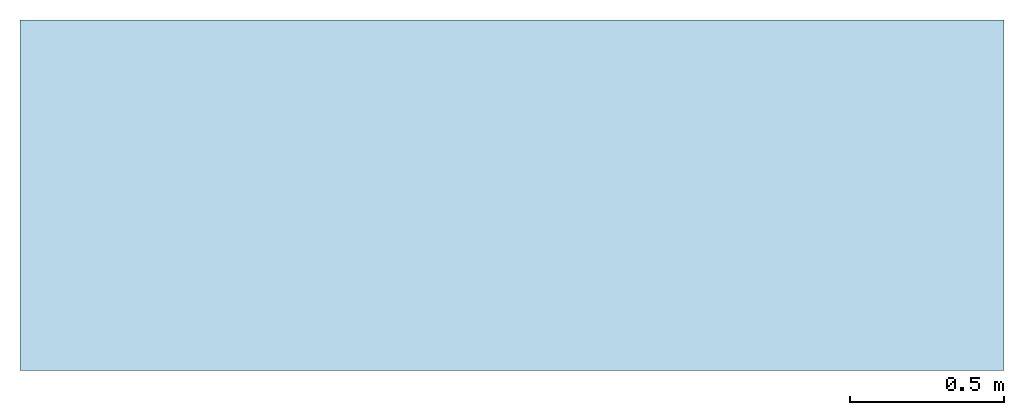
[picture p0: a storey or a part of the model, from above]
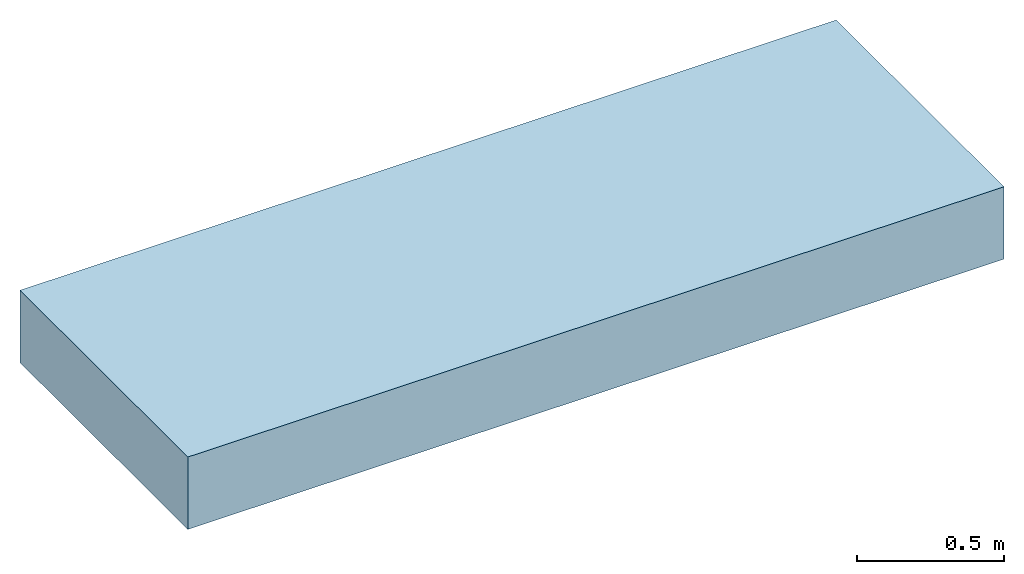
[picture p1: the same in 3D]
Properties of the parts of a building model (IFC2X3)

# File
Description: ViewDefinition [CoordinationView_V2.0, QuantityTakeOffAddOnView], RevitIdentifiers [ContentGUID: 704ee8e6-b7a5-4cdf-b516-c9cadaf13e75, VersionGUID: 9f17e6e7-f3a3-40c8-a4d2-a42c9d882847, NumberOfSaves: 43], CoordinateReference [CoordinateBase: Shared Coordinates, ProjectSite: Internal]
File name: Solucion panel prefabricado stud frame.ifc
Time: 2026-03-16T14:00:17+01:00
Written by: ODA SDAI 24.6
Made in: Autodesk Revit 24.3.40.26 (ESP) - IFC 24.3.20.0

# IfcProject, 000000
LongName: Solución panel prefabricado stud frame

# IfcSite, Default
RefLatitude: 40, 25, 13, 9643; RefLongitude: -3, -42, -20, -772056; RefElevation: 0 m
Otra - Categoría: Información de proyecto; Dirección de proyecto: Parque Empresarial de A Pontenova , Parcelas 33-39 , 27720 · A Pontenova · (Lugo); Fecha de emisión de proyecto: 09-02-2026; Nombre de cliente: Recense; Nombre de proyecto: Solución panel prefabricado stud frame; Número de proyecto: 000000
Datos de identidad - Autor: Deliprogal; Descripción de organización: Fijaciones a medida para prefabricado; Nombre de organización: Recense

# IfcBuilding
Pset_BuildingCommon - NumberOfStoreys: 2
Otra - Categoría: Información de proyecto; Dirección de proyecto: Parque Empresarial de A Pontenova , Parcelas 33-39 , 27720 · A Pontenova · (Lugo); Fecha de emisión de proyecto: 09-02-2026; Nombre de cliente: Recense; Nombre de proyecto: Solución panel prefabricado stud frame; Número de proyecto: 000000
Datos de identidad - Autor: Deliprogal; Descripción de organización: Fijaciones a medida para prefabricado; Nombre de organización: Recense

# IfcBuildingStorey: Nivel:8mm Head (2)
Otra - Categoría: Niveles; Familia: Nivel; Familia y tipo: Nivel: 8mm Head; ID de tipo: 305; Tipo: 8mm Head
Cotas - Altura de cálculo: 0 m
Datos de identidad - Estructura: no; Planta de edificio: yes
Otra(Tipo) - Categoría: Niveles; Nombre de familia: Nivel
Restricciones(Tipo) - Base de elevación: Punto base del proyecto
Gráficos(Tipo) - Color: 12615680; Grosor de línea: 1; Patrón de línea: Dash dot; Símbolo en extremo 1 por defecto: no; Símbolo en extremo 2 por defecto: yes
Datos de identidad(Tipo) - Nombre de tipo: 8mm Head
Name | LongName = Nombre | Elevation (m) = Elevación (m)
L0 | L0 | 0
L1 | L1 | 3

# IfcBuildingElementProxy: Panel Hormigón:Panel Hormigón, Panel Hormigón:Panel Hormigón:3763083
In: L0
Type - Material: Hormigón reforzado con fibra de vidrio, Acero AISI 1022
Type - Otra - Categoría: Modelos genéricos; Nombre de familia: Panel Hormigón
Type - Restricciones - Elevación por defecto: 13.1234 m
Type - Datos de identidad - Nombre de tipo: Panel Hormigón
Pset_BuildingElementProxyCommon - Reference: Panel Hormigón; sets with these values: 2
Otra - Familia: Panel Hormigón; Familia y tipo: Panel Hormigón: Panel Hormigón; ID de tipo: 3674676; Tipo: Panel Hormigón
Restricciones - Desfase desde el anfitrión: -0.15 m; Elevación desde el nivel: 0 m; Plano de trabajo: <no asociado>
Cotas - Área: 14.7895 m2; Volumen: 0.111377 m3
Proceso por fases - Fase de creación: New

# IfcCovering: Techo compuesto:Aislamiento, Techo compuesto:Aislamiento:3635725
In: L0
Type - PredefinedType: CEILING
Type - Otra - Categoría: Techos; Nombre de familia: Techo compuesto
Type - Construcción - Grosor: 0.08 m
Type - Gráficos - Color de relleno de detalle bajo: 0
Type - Datos de identidad - Nombre de tipo: Aislamiento
Type - Propiedades analíticas - Absortancia: 0.7; Aspereza: 3; Coeficiente de transferencia de calor (U): 0.425 kg/K/s3; Masa térmica: 11360 kg/K/s2; Resistencia térmica (R): 2.35294 s3*K/kg
Type - Pset_CoveringCommon - TotalThickness: 0.08 m
Material: Lana de roca 0.08 m
Pset_CoveringCommon - Reference: Aislamiento; sets with these values: 2
BaseQuantities - GrossCeilingArea: 1.4356 m2
Otra - Familia: Techo compuesto; Familia y tipo: Techo compuesto: Aislamiento; ID de tipo: 3635518; Tipo: Aislamiento
Restricciones - Delimitación de habitación: yes; Nivel: L0; Desfase de altura desde nivel: 2.61 m
Cotas - Área: 1.4356 m2; Perímetro: 4.9 m; Volumen: 0.114848 m3
Proceso por fases - Fase de creación: New

# IfcCovering: Techo compuesto:Placa, Techo compuesto:Placa:3635732
In: L0
Type - PredefinedType: CEILING
Type - Otra - Categoría: Techos; Nombre de familia: Techo compuesto
Type - Construcción - Grosor: 0.01 m
Type - Gráficos - Color de relleno de detalle bajo: 0
Type - Datos de identidad - Nombre de tipo: Placa
Type - Propiedades analíticas - Absortancia: 0.7; Aspereza: 3; Coeficiente de transferencia de calor (U): 51 kg/K/s3; Masa térmica: 10752 kg/K/s2; Resistencia térmica (R): 0.0196078 s3*K/kg
Type - Pset_CoveringCommon - TotalThickness: 0.01 m
Material: Enlucido 0.01 m
Pset_CoveringCommon - Reference: Placa; Finish: Enlucido;
Pset_QuantityTakeOff - Reference: Placa
BaseQuantities - GrossCeilingArea: 1.2672 m2
Otra - Familia: Techo compuesto; Familia y tipo: Techo compuesto: Placa; ID de tipo: 3635581; Tipo: Placa
Restricciones - Delimitación de habitación: yes; Nivel: L0; Desfase de altura desde nivel: 2.6 m
Cotas - Área: 1.2672 m2; Perímetro: 4.56 m; Volumen: 0.012672 m3
Proceso por fases - Fase de creación: New

# IfcElementAssembly: REC-AEM12-100:AEM12-100 (2)
In: L0
Type - Material: REC_Acero, S 275JR (Zincado)
Type - Otra - Categoría: Conexiones estructurales; Nombre de familia: REC-AEM12-100
Type - Restricciones - Elevación por defecto: 0 m
Type - Datos - Classification.Uniclass.Pr.Description: Bolts and accessories; Classification.Uniclass.Pr.Number: Pr_20_29_08
Type - Datos de identidad - Costo: 0; Creado por:: Deliprogal SL; Descripción: Anclaje M12; Fabricante: RECENSE; Fecha de Creacion:: 12/12/2025; Fecha Ultima Revision:: 16/03/2026; Modelo: AEM12-100; Nombre de tipo: AEM12-100; URL: https://recense.com/
Pset_QuantityTakeOff - Reference: AEM12-100
Otra - Familia: REC-AEM12-100; Familia y tipo: REC-AEM12-100: AEM12-100; ID de tipo: 3834086; Tipo: AEM12-100
Restricciones - Anfitrión: Panel Hormigón : Panel Hormigón; Se mueve con elementos cercanos: no
Datos - DPG_FABRICA: IL; DPG_NUMERO_OT: OT-
Cotas - Área: 0.00338965 m2; Volumen: 0.0000142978 m3
Proceso por fases - Fase de creación: New
Name (REC-AEM12-100:AEM12-100:...)
3767526
3793628

# IfcElementAssembly: REC-AEM12-140:AEM12-140 (2)
In: L0
Type - Material: REC_Acero, S 275JR (Zincado)
Type - Otra - Categoría: Conexiones estructurales; Nombre de familia: REC-AEM12-140
Type - Restricciones - Elevación por defecto: 0 m
Type - Datos - Classification.Uniclass.Pr.Description: Bolts and accessories; Classification.Uniclass.Pr.Number: Pr_20_29_08
Type - Datos de identidad - Costo: 0; Creado por:: Deliprogal SL; Descripción: https://recense.com/; Description_ESP: Anclaje M12; Fabricante: RECENSE; Fecha de Creacion:: 12/12/2025; Fecha Ultima Revision:: 16/03/2026; Modelo: AEM12-140; Nombre de tipo: AEM12-140
Pset_QuantityTakeOff - Reference: AEM12-140
Otra - Familia: REC-AEM12-140; Familia y tipo: REC-AEM12-140: AEM12-140; ID de tipo: 3781469; Tipo: AEM12-140
Restricciones - Se mueve con elementos cercanos: no; Anfitrión: Panel Hormigón : Panel Hormigón
Cotas - Área: 0.00414363 m2; Volumen: 0.0000188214 m3
Proceso por fases - Fase de creación: New
Name (REC-AEM12-140:AEM12-140:...)
3776366
3793606

# IfcElementAssembly: REC-AU12050M8EQ:AU12050M8EQ (4)
In: L0
Type - Material: REC_Acero, S 275JR (Zincado)
Type - Otra - Categoría: Conexiones estructurales; Nombre de familia: REC-AU12050M8EQ
Type - Restricciones - Elevación por defecto: 0 m
Type - Datos - Classification.Uniclass.Pr.Description: Anchors and componentsAnchors and components; Classification.Uniclass.Pr.Number: Pr_20_29_03
Type - Datos de identidad - Costo: 0; Creado por:: Deliprogal SL; Descripción: U-bolt M-8 120x50 mm equipped.; Description_ESP: Abarcón en U M-8 120x50 mm equipado.; Fabricante: RECENSE; Fecha de Creacion:: 03/02/2026; Fecha Ultima Revision:: 16/03/2026; Keynote_ESP: Sistema portante para sustentación de paneles de hormigón GRC tipo STUDFRAME en paramentos verticales.; Modelo: AU10040M8EQ; Nombre de tipo: AU12050M8EQ; Nota clave: Supporting system for fixing GRC STUDFRAME type panels to walls or other vertical concrete surface.; URL: https://abarcones.recense.com/ar/abarcones/abarcones-cuadrados/
Pset_QuantityTakeOff - Reference: AU12050M8EQ
Otra - Familia: REC-AU12050M8EQ; Familia y tipo: REC-AU12050M8EQ: AU12050M8EQ; ID de tipo: 3767338; Tipo: AU12050M8EQ
Restricciones - Se mueve con elementos cercanos: no; Anfitrión: Panel Hormigón : Panel Hormigón
Cotas - Área: 0.00322422 m2; Volumen: 0.00001157 m3
Proceso por fases - Fase de creación: New
Name (REC-AU12050M8EQ:AU12050M8EQ:...) | DPG_FOR_POS_ABARCON (m) = DPG_POS_ABARCON (m)
3767527 | 0.086
3776364 | 0.0965
3793605 | 0.0965
3793629 | 0.086

# IfcElementAssembly: REC-PA200406R:PA200406R (2)
In: L0
Type - Material: REC_Acero, S 275JR (Zincado)
Type - Otra - Categoría: Conexiones estructurales; Nombre de familia: REC-PA200406R
Type - Restricciones - Elevación por defecto: 0 m
Type - Datos - Classification.Uniclass.Pr.Description: Carbon steel anchor plates; Classification.Uniclass.Pr.Number: Pr_20_29_03_10
Type - Datos de identidad - Costo: 0; Creado por:: Deliprogal SL; Descripción: Angle plate 200x40x40x80x6 mm 2 slotted holes 15x9 mm.; Description_ESP: Pletina angular 200x40x80x6 mm 2 ranuras 15x9 mm.; Fabricante: RECENSE; Fecha de Creacion:: 20/01/2026; Fecha Ultima Revision:: 09/02/2026; Keynote_ESP: Sistema antivuelco para paneles de hormigón GRC tipo STUD FRAME.; Modelo: PA200406R; Nombre de tipo: PA200406R; Nota clave: Anti-tilt system for GRC concrete panels type STUD FRAME.; URL: https://prefabricados.recense.com/prefabricados/fijacion/fijacion-grc/grc-studframe/anclajes-antivuelco/pa200406r/
Pset_QuantityTakeOff - Reference: PA200406R
Otra - Familia: REC-PA200406R; Familia y tipo: REC-PA200406R: PA200406R; ID de tipo: 3767337; Tipo: PA200406R
Restricciones - Se mueve con elementos cercanos: no; Anfitrión: Ninguno
Cotas - Área: 0.0203081 m2; Volumen: 0.000107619 m3
Proceso por fases - Fase de creación: New
Name (REC-PA200406R:PA200406R:...)
3849143
3849144

# IfcElementAssembly: REC-PAA2005010R:PAA2005010R (2)
In: L0
Type - Material: REC_Acero, S 275JR (Zincado)
Type - Otra - Categoría: Conexiones estructurales; Nombre de familia: REC-PAA2005010R
Type - Restricciones - Elevación por defecto: 0 m
Type - Datos - Classification.Uniclass.Pr.Description: Carbon steel anchor plates; Classification.Uniclass.Pr.Number: Pr_20_29_03_10
Type - Datos de identidad - Costo: 0; Creado por:: Deliprogal SL; Descripción: Non-slip angle plate 200x50x80x80x10 mm with 2 slotted holes 15x9 mm.; Description_ESP: Pletina angular antideslizante 200x50x80x10 mm 2 ranuras 15x9 mm.; Fabricante: RECENSE; Fecha de Creacion:: 02/02/2026; Fecha Ultima Revision:: 09/02/2026; Keynote_ESP: Sistema de ménsula portante para paneles de hormigón GRC tipo STUD FRAME.; Modelo: PAA2005010R; Nombre de tipo: PAA2005010R; Nota clave: Supporting bracket system for GRC concrete panelsGRC concrete panels STUD FRAME type.; URL: https://prefabricados.recense.com/prefabricados/fijacion/fijacion-grc/grc-studframe/mensulas-portantes/paa2005010r/
Pset_QuantityTakeOff - Reference: PAA2005010R
Otra - Familia: REC-PAA2005010R; Familia y tipo: REC-PAA2005010R: PAA2005010R; ID de tipo: 3776105; Tipo: PAA2005010R
Restricciones - Se mueve con elementos cercanos: no
Cotas - Área: 0.0227408 m2; Volumen: 0.000180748 m3
Proceso por fases - Fase de creación: New
Name (REC-PAA2005010R:PAA2005010R:...) | Anfitrión
3781703 | Ninguno
3793610 | Panel Hormigón : Panel Hormigón

# IfcElementAssembly: REC-PD120308:PD120308 (2)
In: L0
Type - Material: REC_Acero, S 275JR (Zincado)
Type - Otra - Categoría: Conexiones estructurales; Nombre de familia: REC-PD120308
Type - Restricciones - Elevación por defecto: 0 m
Type - Datos - Classification.Uniclass.Pr.Description: Carbon steel anchor plates; Classification.Uniclass.Pr.Number: Pr_20_29_03_10
Type - Datos de identidad - Costo: 0; Creado por:: Deliprogal SL; Descripción: Toothed plate 120x30x8 mm.; Description_ESP: Pletina dentada 120x30x8 mm.; Fabricante: RECENSE; Fecha de Creacion:: 02/02/2026; Fecha Ultima Revision:: 09/02/2026; Keynote_ESP: Sistema de sustentación a forjado mediante anclajes portantes y antivuelco para paneles prefabricados de hormigón GRC tipo Studframe.; Modelo: PD120308; Nombre de tipo: PD120308; Nota clave: Supporting system for slab by means of load-bearing and anti-overturning anchors for precast concrete panels GRC Studframe type.; URL: https://prefabricados.recense.com/prefabricados/fijacion/fijacion-grc/grc-studframe/mensulas-portantes/paa2005010r/
Type - Texto - DPG_ANCLAJE_TIPO: ANCLAJE
Pset_QuantityTakeOff - Reference: PD120308
Otra - Familia: REC-PD120308; Familia y tipo: REC-PD120308: PD120308; ID de tipo: 3776109; Tipo: PD120308
Restricciones - Se mueve con elementos cercanos: no
Cotas - Área: 0.00536558 m2; Volumen: 0.0000252 m3
Proceso por fases - Fase de creación: New
Name (REC-PD120308:PD120308:...) | Anfitrión
3781702 | Ninguno
3793609 | Panel Hormigón : Panel Hormigón

# IfcFurnishingElement: REC_A_M8:REC_A_M8 (8)
In: L0
Type - Material: REC_Acero, S 275JR (Zincado)
Type - Otra - Categoría: Conexiones estructurales; Nombre de familia: REC_A_M8
Type - Restricciones - Elevación por defecto: 13.1234 m
Type - Datos de identidad - Modelo: A-M10; Nombre de tipo: REC_A_M8; URL: https://prefabricados.recense.com/prefabricados/fijacion/fijacion-grc/grc-studframe/anclajes-antivuelco/pa200406r/
Pset_QuantityTakeOff - Reference: REC_A_M8
Otra - Familia: REC_A_M8; Familia y tipo: REC_A_M8: REC_A_M8; ID de tipo: 3834089; Tipo: REC_A_M8
Restricciones - Se mueve con elementos cercanos: no; Anfitrión: Panel Hormigón : Panel Hormigón
Cotas - Área: 0.000324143 m2; Volumen: 6.24619e-07 m3
Proceso por fases - Fase de creación: New
Estructura - Recubrimiento de armadura: Rebar Cover 1 <25 mm>
Name (REC_A_M8:REC_A_M8:...) | Desfase desde el anfitrión (m)
3767528 | -0.010004
3767529 | -0.010004
3776367 | -0.0536447
3776368 | -0.0536447
3793607 | -0.0536447
3793608 | -0.0536447
3793630 | -0.010004
3793631 | -0.010004

# IfcOpeningElement: Opening (8)
In: L0
BaseQuantities - Depth: 0.08 m; Area: 0.00138596 m2
Pset_OpeningElementCommon - Reference: PA200406R; sets with these values: 2
Name (REC-PA200406R:PA200406R:...)
3849143:1
3849143:2
3849143:3
3849143:4
3849144:1
3849144:2
3849144:3
3849144:4

# IfcSlab: Suelo:DPG_Aislamiento Suelo, Suelo:DPG_Aislamiento Suelo:3607158
In: L0
Type - PredefinedType: FLOOR; Material: Lana de roca 0.04 m
Type - Otra - Categoría: Suelos; Nombre de familia: Suelo
Type - Construcción - Función: Interior; Grosor predeterminado: 0.04 m
Type - Gráficos - Color de relleno de detalle bajo: 0
Type - Datos de identidad - Nombre de tipo: DPG_Aislamiento Suelo
Type - Materiales y acabados - Material estructural: Lana de roca
Type - Propiedades analíticas - Absortancia: 0.7; Aspereza: 3; Coeficiente de transferencia de calor (U): 0.85 kg/K/s3; Masa térmica: 5680 kg/K/s2; Resistencia térmica (R): 1.17647 s3*K/kg
Type - Pset_SlabCommon - ThermalTransmittance: 0.85 kg/K/s3
Pset_QuantityTakeOff - Reference: DPG_Aislamiento Suelo; sets with these values: 2
Pset_SlabCommon - IsExternal: no; LoadBearing: no; PitchAngle: 0 deg; Reference: DPG_Aislamiento Suelo
BaseQuantities - Width: 1.64 m; Perimeter: 5.22 m; GrossArea: 1.5908 m2; NetArea: 1.5908 m2; GrossVolume: 0.063632 m3; NetVolume: 0.063632 m3
Otra - Familia: Suelo; Familia y tipo: Suelo: DPG_Aislamiento Suelo; ID de tipo: 3607200; Tipo: DPG_Aislamiento Suelo
Restricciones - Delimitación de habitación: yes; Nivel: L0; Relacionado con masa: no; Desfase de altura desde nivel: 0.04 m
Cotas - Área: 1.5908 m2; Elevación en parte inferior: 0 m; Elevación en parte inferior de núcleo: 0 m; Elevación en parte superior: 0.04 m; Elevación en parte superior de núcleo: 0.04 m; Grosor: 0.04 m; Perímetro: 5.22 m; Volumen: 0.063632 m3
Datos de identidad - Tiene asociación: no
Proceso por fases - Fase de creación: New
Estructura - Estructura: no

# IfcSlab: Suelo:DPG_Ceramica, Suelo:DPG_Ceramica:3607525
In: L0
Type - PredefinedType: FLOOR; Material: Azulejo, porcelana, 6 pulg. 0.01 m
Type - Otra - Categoría: Suelos; Nombre de familia: Suelo
Type - Construcción - Función: Interior; Grosor predeterminado: 0.01 m
Type - Gráficos - Color de relleno de detalle bajo: 0
Type - Datos de identidad - Nombre de tipo: DPG_Ceramica
Type - Materiales y acabados - Material estructural: Azulejo, porcelana, 6 pulg.
Type - Propiedades analíticas - Absortancia: 0.7; Aspereza: 3; Coeficiente de transferencia de calor (U): 120 kg/K/s3; Masa térmica: 17000 kg/K/s2; Resistencia térmica (R): 0.00833333 s3*K/kg
Type - Pset_SlabCommon - ThermalTransmittance: 120 kg/K/s3
Pset_QuantityTakeOff - Reference: DPG_Ceramica; sets with these values: 2
Pset_SlabCommon - IsExternal: no; LoadBearing: no; PitchAngle: 0 deg; Reference: DPG_Ceramica
BaseQuantities - Width: 1.32 m; Perimeter: 4.58 m; GrossArea: 1.2804 m2; NetArea: 1.2804 m2; GrossVolume: 0.012804 m3; NetVolume: 0.012804 m3
Otra - Familia: Suelo; Familia y tipo: Suelo: DPG_Ceramica; ID de tipo: 3607552; Tipo: DPG_Ceramica
Restricciones - Delimitación de habitación: yes; Nivel: L0; Relacionado con masa: no; Desfase de altura desde nivel: 0.11 m
Cotas - Área: 1.2804 m2; Elevación en parte inferior: 0.1 m; Elevación en parte inferior de núcleo: 0.1 m; Elevación en parte superior: 0.11 m; Elevación en parte superior de núcleo: 0.11 m; Grosor: 0.01 m; Perímetro: 4.58 m; Volumen: 0.012804 m3
Datos de identidad - Tiene asociación: no
Proceso por fases - Fase de creación: New
Estructura - Estructura: no

# IfcSlab: Suelo:DPG_Losa Principal Obra (2)
Type - PredefinedType: FLOOR; Material: DPG_Losa Principal Obra 0.3 m
Type - Otra - Categoría: Suelos; Nombre de familia: Suelo
Type - Construcción - Función: Interior; Grosor predeterminado: 0.3 m
Type - Gráficos - Color de relleno de detalle bajo: 0
Type - Datos de identidad - Nombre de tipo: DPG_Losa Principal Obra
Type - Materiales y acabados - Material estructural: DPG_Losa Principal Obra
Type - Propiedades analíticas - Absortancia: 0.7; Aspereza: 3
Pset_QuantityTakeOff - Reference: DPG_Losa Principal Obra; sets with these values: 2
Pset_SlabCommon - Reference: DPG_Losa Principal Obra; IsExternal: no; LoadBearing: no; PitchAngle: 0 deg
BaseQuantities - Width: 3.2 m; Perimeter: 8.68 m; GrossArea: 3.648 m2; NetArea: 3.648 m2; GrossVolume: 1.0944 m3; NetVolume: 1.0944 m3
Otra - Familia: Suelo; Familia y tipo: Suelo: DPG_Losa Principal Obra; ID de tipo: 759; Tipo: DPG_Losa Principal Obra
Restricciones - Delimitación de habitación: yes; Relacionado con masa: no
Cotas - Área: 3.648 m2; Grosor: 0.3 m; Perímetro: 8.68 m; Volumen: 1.0944 m3
Datos de identidad - Tiene asociación: no
Proceso por fases - Fase de creación: New
Estructura - Estructura: no
Name (Suelo:DPG_Losa Principal Obra:...) | In | Desfase de altura desde nivel (m) | Nivel | Elevación en parte inferior (m) = Elevación en parte inferior de núcleo (m) | Elevación en parte superior (m) = Elevación en parte superior de núcleo (m)
3592091 | L0 | 0 | L0 | -0.3 | 0
3645118 | L1 | 0.02 | L1 | 2.72 | 3.02

# IfcSlab: Suelo:DPG_Pegamento cemento, Suelo:DPG_Pegamento cemento:3607421
In: L0
Type - PredefinedType: FLOOR; Material: Hormigón - Hormigón moldeado in situ 0.01 m
Type - Otra - Categoría: Suelos; Nombre de familia: Suelo
Type - Construcción - Función: Interior; Grosor predeterminado: 0.01 m
Type - Gráficos - Color de relleno de detalle bajo: 0
Type - Datos de identidad - Nombre de tipo: DPG_Pegamento cemento
Type - Materiales y acabados - Material estructural: Hormigón - Hormigón moldeado in situ
Type - Propiedades analíticas - Absortancia: 0.7; Aspereza: 3
Pset_QuantityTakeOff - Reference: DPG_Pegamento cemento; sets with these values: 2
Pset_SlabCommon - IsExternal: no; LoadBearing: no; PitchAngle: 0 deg; Reference: DPG_Pegamento cemento
BaseQuantities - Width: 1.44 m; Perimeter: 4.82 m; GrossArea: 1.3968 m2; NetArea: 1.3968 m2; GrossVolume: 0.013968 m3; NetVolume: 0.013968 m3
Otra - Familia: Suelo; Familia y tipo: Suelo: DPG_Pegamento cemento; ID de tipo: 3607442; Tipo: DPG_Pegamento cemento
Restricciones - Delimitación de habitación: yes; Nivel: L0; Relacionado con masa: no; Desfase de altura desde nivel: 0.1 m
Cotas - Área: 1.3968 m2; Elevación en parte inferior: 0.09 m; Elevación en parte inferior de núcleo: 0.09 m; Elevación en parte superior: 0.1 m; Elevación en parte superior de núcleo: 0.1 m; Grosor: 0.01 m; Perímetro: 4.82 m; Volumen: 0.013968 m3
Datos de identidad - Tiene asociación: no
Proceso por fases - Fase de creación: New
Estructura - Estructura: no

# IfcSlab: Suelo:DPG_Recrecido, Suelo:DPG_Recrecido:3607293
In: L0
Type - PredefinedType: FLOOR; Material: Hormigón, ligero 0.05 m
Type - Otra - Categoría: Suelos; Nombre de familia: Suelo
Type - Construcción - Función: Interior; Grosor predeterminado: 0.05 m
Type - Gráficos - Color de relleno de detalle bajo: 0
Type - Datos de identidad - Nombre de tipo: DPG_Recrecido
Type - Materiales y acabados - Material estructural: Hormigón, ligero
Type - Propiedades analíticas - Absortancia: 0.7; Aspereza: 3; Coeficiente de transferencia de calor (U): 4.18 kg/K/s3; Masa térmica: 31207.5 kg/K/s2; Resistencia térmica (R): 0.239234 s3*K/kg
Type - Pset_SlabCommon - ThermalTransmittance: 4.18 kg/K/s3
Pset_QuantityTakeOff - Reference: DPG_Recrecido; sets with these values: 2
Pset_SlabCommon - IsExternal: no; LoadBearing: no; PitchAngle: 0 deg; Reference: DPG_Recrecido
BaseQuantities - Width: 1.54 m; Perimeter: 5.02 m; GrossArea: 1.4938 m2; NetArea: 1.4938 m2; GrossVolume: 0.07469 m3; NetVolume: 0.07469 m3
Otra - Familia: Suelo; Familia y tipo: Suelo: DPG_Recrecido; ID de tipo: 3607308; Tipo: DPG_Recrecido
Restricciones - Delimitación de habitación: yes; Nivel: L0; Relacionado con masa: no; Desfase de altura desde nivel: 0.09 m
Cotas - Área: 1.4938 m2; Elevación en parte inferior: 0.04 m; Elevación en parte inferior de núcleo: 0.04 m; Elevación en parte superior: 0.09 m; Elevación en parte superior de núcleo: 0.09 m; Grosor: 0.05 m; Perímetro: 5.02 m; Volumen: 0.07469 m3
Datos de identidad - Tiene asociación: no
Proceso por fases - Fase de creación: New
Estructura - Estructura: no

# IfcWallStandardCase: Muro básico:DPG_Aislamiento, Muro básico:DPG_Aislamiento:3607087
In: L0
Type - PredefinedType: STANDARD; Material: Lana de roca 0.1 m
Type - Otra - Categoría: Muros; Nombre de familia: Muro básico
Type - Construcción - Anchura: 0.1 m; Envolvente en extremos: Ninguno; Envolvente en inserciones: Sin envolvente; Función: Retención
Type - Gráficos - Color de relleno de detalle bajo: 0
Type - Datos de identidad - Nombre de tipo: DPG_Aislamiento
Type - Propiedades analíticas - Absortancia: 0.7; Aspereza: 3; Coeficiente de transferencia de calor (U): 0.34 kg/K/s3; Masa térmica: 14200 kg/K/s2; Resistencia térmica (R): 2.94118 s3*K/kg
Type - Pset_WallCommon - ThermalTransmittance: 0.34 kg/K/s3
BaseQuantities - Height: 2.72 m; Length: 1.76 m; Width: 0.1 m; GrossFootprintArea: 0.176 m2; GrossVolume: 0.47872 m3; GrossSideArea: 4.7872 m2; NetSideArea: 4.7872 m2; NetVolume: 0.47872 m3
Pset_QuantityTakeOff - Reference: DPG_Aislamiento; sets with these values: 2
Pset_WallCommon - LoadBearing: no; Reference: DPG_Aislamiento; IsExternal: yes; ExtendToStructure: no
Otra - Familia: Muro básico; Familia y tipo: Muro básico: DPG_Aislamiento; ID de tipo: 3607102; Tipo: DPG_Aislamiento
Restricciones - Relacionado con masa: no; Altura desconectada: 2.72 m; Delimitación de habitación: no; Desfase de base: 0 m; Desfase superior: 0 m; Distancia de extensión de base: 0 m; Distancia de extensión superior: 0 m; La base está enlazada: no; La parte superior está enlazada: no; Línea de ubicación: Cara de acabado: Exterior; Restricción de base: L0
Cotas - Área: 4.7872 m2; Longitud: 1.76 m; Volumen: 0.47872 m3
Proceso por fases - Fase de creación: New
Estructura - Estructura: no; Uso estructural: No portante
Definición de sección transversal - Sección transversal: Vertical

# IfcWallStandardCase: Muro básico:DPG_Enlucido, Muro básico:DPG_Enlucido:3608548
In: L0
Type - PredefinedType: STANDARD; Material: Enlucido 0.01 m
Type - Otra - Categoría: Muros; Nombre de familia: Muro básico
Type - Construcción - Envolvente en extremos: Ninguno; Envolvente en inserciones: Sin envolvente; Función: Retención; Anchura: 0.01 m
Type - Gráficos - Color de relleno de detalle bajo: 0
Type - Datos de identidad - Nombre de tipo: DPG_Enlucido
Type - Propiedades analíticas - Absortancia: 0.7; Aspereza: 3; Coeficiente de transferencia de calor (U): 51 kg/K/s3; Masa térmica: 10752 kg/K/s2; Resistencia térmica (R): 0.0196078 s3*K/kg
Type - Pset_WallCommon - ThermalTransmittance: 51 kg/K/s3
BaseQuantities - Height: 2.5 m; Length: 1.32 m; Width: 0.01 m; GrossFootprintArea: 0.0132 m2; GrossVolume: 0.033 m3; GrossSideArea: 3.3 m2; NetSideArea: 3.3 m2; NetVolume: 0.033 m3
Pset_QuantityTakeOff - Reference: DPG_Enlucido; sets with these values: 2
Pset_WallCommon - LoadBearing: no; IsExternal: yes; ExtendToStructure: no; Reference: DPG_Enlucido
Otra - Familia: Muro básico; Familia y tipo: Muro básico: DPG_Enlucido; ID de tipo: 3608303; Tipo: DPG_Enlucido
Restricciones - Relacionado con masa: no; Delimitación de habitación: no; Desfase superior: 0 m; Distancia de extensión de base: 0 m; Distancia de extensión superior: 0 m; La base está enlazada: no; La parte superior está enlazada: no; Línea de ubicación: Cara de acabado: Exterior; Restricción de base: L0; Altura desconectada: 2.5 m; Desfase de base: 0.11 m
Cotas - Área: 3.3 m2; Longitud: 1.32 m; Volumen: 0.033 m3
Proceso por fases - Fase de creación: New
Estructura - Estructura: no; Uso estructural: No portante
Definición de sección transversal - Sección transversal: Vertical

# IfcWallStandardCase: Muro básico:DPG_Ladrillo, Muro básico:DPG_Ladrillo:3607614
In: L0
Type - PredefinedType: STANDARD; Material: Ladrillo, común, marrón 0.07 m
Type - Otra - Categoría: Muros; Nombre de familia: Muro básico
Type - Construcción - Envolvente en extremos: Ninguno; Envolvente en inserciones: Sin envolvente; Función: Retención; Anchura: 0.07 m
Type - Gráficos - Color de relleno de detalle bajo: 0
Type - Datos de identidad - Nombre de tipo: DPG_Ladrillo
Type - Propiedades analíticas - Absortancia: 0.7; Aspereza: 3; Coeficiente de transferencia de calor (U): 7.71429 kg/K/s3; Masa térmica: 91140 kg/K/s2; Resistencia térmica (R): 0.12963 s3*K/kg
Type - Pset_WallCommon - ThermalTransmittance: 7.71429 kg/K/s3
BaseQuantities - Height: 2.72 m; Length: 1.64 m; Width: 0.07 m; GrossFootprintArea: 0.1148 m2; GrossVolume: 0.312256 m3; GrossSideArea: 4.4608 m2; NetSideArea: 4.4608 m2; NetVolume: 0.312256 m3
Pset_QuantityTakeOff - Reference: DPG_Ladrillo; sets with these values: 2
Pset_WallCommon - LoadBearing: no; IsExternal: yes; ExtendToStructure: no; Reference: DPG_Ladrillo
Otra - Familia: Muro básico; Familia y tipo: Muro básico: DPG_Ladrillo; ID de tipo: 3607732; Tipo: DPG_Ladrillo
Restricciones - Relacionado con masa: no; Delimitación de habitación: no; Desfase de base: 0 m; Desfase superior: 0 m; Distancia de extensión de base: 0 m; Distancia de extensión superior: 0 m; La base está enlazada: no; La parte superior está enlazada: no; Línea de ubicación: Cara de acabado: Exterior; Restricción de base: L0; Altura desconectada: 2.72 m
Cotas - Área: 4.4608 m2; Longitud: 1.64 m; Volumen: 0.312256 m3
Proceso por fases - Fase de creación: New
Estructura - Estructura: no; Uso estructural: No portante
Definición de sección transversal - Sección transversal: Vertical
